# Generated by FakeRAM 2.0
VERSION 5.7 ;
BUSBITCHARS "[]" ;
PROPERTYDEFINITIONS
  MACRO width INTEGER ;
  MACRO depth INTEGER ;
  MACRO banks INTEGER ;
END PROPERTYDEFINITIONS
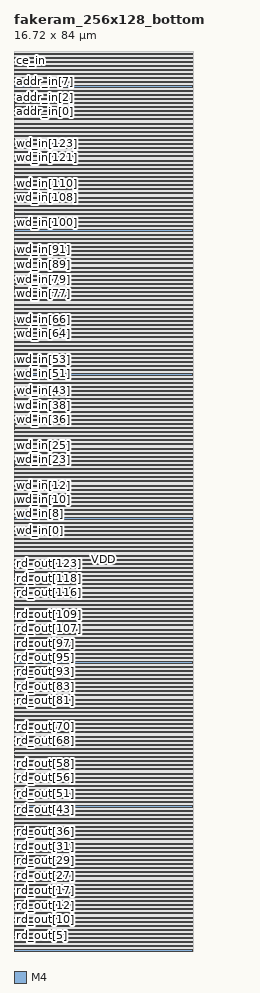
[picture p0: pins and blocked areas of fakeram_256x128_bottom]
MACRO fakeram_256x128_bottom
  PROPERTY width 128 ;
  PROPERTY depth 256 ;
  PROPERTY banks 1 ;
  FOREIGN fakeram_256x128_bottom 0 0 ;
  SYMMETRY X Y R90 ;
  SIZE 16.720 BY 84.000 ;
  CLASS BLOCK ;
  PIN rd_out[0]
    DIRECTION OUTPUT ;
    USE SIGNAL ;
    SHAPE ABUTMENT ;
    PORT
      LAYER M4 ;
      RECT 0.000 0.039 0.024 0.063 ;
    END
  END rd_out[0]
  PIN rd_out[1]
    DIRECTION OUTPUT ;
    USE SIGNAL ;
    SHAPE ABUTMENT ;
    PORT
      LAYER M4 ;
      RECT 0.000 0.327 0.024 0.351 ;
    END
  END rd_out[1]
  PIN rd_out[2]
    DIRECTION OUTPUT ;
    USE SIGNAL ;
    SHAPE ABUTMENT ;
    PORT
      LAYER M4 ;
      RECT 0.000 0.615 0.024 0.639 ;
    END
  END rd_out[2]
  PIN rd_out[3]
    DIRECTION OUTPUT ;
    USE SIGNAL ;
    SHAPE ABUTMENT ;
    PORT
      LAYER M4 ;
      RECT 0.000 0.903 0.024 0.927 ;
    END
  END rd_out[3]
  PIN rd_out[4]
    DIRECTION OUTPUT ;
    USE SIGNAL ;
    SHAPE ABUTMENT ;
    PORT
      LAYER M4 ;
      RECT 0.000 1.191 0.024 1.215 ;
    END
  END rd_out[4]
  PIN rd_out[5]
    DIRECTION OUTPUT ;
    USE SIGNAL ;
    SHAPE ABUTMENT ;
    PORT
      LAYER M4 ;
      RECT 0.000 1.479 0.024 1.503 ;
    END
  END rd_out[5]
  PIN rd_out[6]
    DIRECTION OUTPUT ;
    USE SIGNAL ;
    SHAPE ABUTMENT ;
    PORT
      LAYER M4 ;
      RECT 0.000 1.767 0.024 1.791 ;
    END
  END rd_out[6]
  PIN rd_out[7]
    DIRECTION OUTPUT ;
    USE SIGNAL ;
    SHAPE ABUTMENT ;
    PORT
      LAYER M4 ;
      RECT 0.000 2.055 0.024 2.079 ;
    END
  END rd_out[7]
  PIN rd_out[8]
    DIRECTION OUTPUT ;
    USE SIGNAL ;
    SHAPE ABUTMENT ;
    PORT
      LAYER M4 ;
      RECT 0.000 2.343 0.024 2.367 ;
    END
  END rd_out[8]
  PIN rd_out[9]
    DIRECTION OUTPUT ;
    USE SIGNAL ;
    SHAPE ABUTMENT ;
    PORT
      LAYER M4 ;
      RECT 0.000 2.631 0.024 2.655 ;
    END
  END rd_out[9]
  PIN rd_out[10]
    DIRECTION OUTPUT ;
    USE SIGNAL ;
    SHAPE ABUTMENT ;
    PORT
      LAYER M4 ;
      RECT 0.000 2.919 0.024 2.943 ;
    END
  END rd_out[10]
  PIN rd_out[11]
    DIRECTION OUTPUT ;
    USE SIGNAL ;
    SHAPE ABUTMENT ;
    PORT
      LAYER M4 ;
      RECT 0.000 3.207 0.024 3.231 ;
    END
  END rd_out[11]
  PIN rd_out[12]
    DIRECTION OUTPUT ;
    USE SIGNAL ;
    SHAPE ABUTMENT ;
    PORT
      LAYER M4 ;
      RECT 0.000 3.495 0.024 3.519 ;
    END
  END rd_out[12]
  PIN rd_out[13]
    DIRECTION OUTPUT ;
    USE SIGNAL ;
    SHAPE ABUTMENT ;
    PORT
      LAYER M4 ;
      RECT 0.000 3.783 0.024 3.807 ;
    END
  END rd_out[13]
  PIN rd_out[14]
    DIRECTION OUTPUT ;
    USE SIGNAL ;
    SHAPE ABUTMENT ;
    PORT
      LAYER M4 ;
      RECT 0.000 4.071 0.024 4.095 ;
    END
  END rd_out[14]
  PIN rd_out[15]
    DIRECTION OUTPUT ;
    USE SIGNAL ;
    SHAPE ABUTMENT ;
    PORT
      LAYER M4 ;
      RECT 0.000 4.359 0.024 4.383 ;
    END
  END rd_out[15]
  PIN rd_out[16]
    DIRECTION OUTPUT ;
    USE SIGNAL ;
    SHAPE ABUTMENT ;
    PORT
      LAYER M4 ;
      RECT 0.000 4.647 0.024 4.671 ;
    END
  END rd_out[16]
  PIN rd_out[17]
    DIRECTION OUTPUT ;
    USE SIGNAL ;
    SHAPE ABUTMENT ;
    PORT
      LAYER M4 ;
      RECT 0.000 4.935 0.024 4.959 ;
    END
  END rd_out[17]
  PIN rd_out[18]
    DIRECTION OUTPUT ;
    USE SIGNAL ;
    SHAPE ABUTMENT ;
    PORT
      LAYER M4 ;
      RECT 0.000 5.223 0.024 5.247 ;
    END
  END rd_out[18]
  PIN rd_out[19]
    DIRECTION OUTPUT ;
    USE SIGNAL ;
    SHAPE ABUTMENT ;
    PORT
      LAYER M4 ;
      RECT 0.000 5.511 0.024 5.535 ;
    END
  END rd_out[19]
  PIN rd_out[20]
    DIRECTION OUTPUT ;
    USE SIGNAL ;
    SHAPE ABUTMENT ;
    PORT
      LAYER M4 ;
      RECT 0.000 5.799 0.024 5.823 ;
    END
  END rd_out[20]
  PIN rd_out[21]
    DIRECTION OUTPUT ;
    USE SIGNAL ;
    SHAPE ABUTMENT ;
    PORT
      LAYER M4 ;
      RECT 0.000 6.087 0.024 6.111 ;
    END
  END rd_out[21]
  PIN rd_out[22]
    DIRECTION OUTPUT ;
    USE SIGNAL ;
    SHAPE ABUTMENT ;
    PORT
      LAYER M4 ;
      RECT 0.000 6.375 0.024 6.399 ;
    END
  END rd_out[22]
  PIN rd_out[23]
    DIRECTION OUTPUT ;
    USE SIGNAL ;
    SHAPE ABUTMENT ;
    PORT
      LAYER M4 ;
      RECT 0.000 6.663 0.024 6.687 ;
    END
  END rd_out[23]
  PIN rd_out[24]
    DIRECTION OUTPUT ;
    USE SIGNAL ;
    SHAPE ABUTMENT ;
    PORT
      LAYER M4 ;
      RECT 0.000 6.951 0.024 6.975 ;
    END
  END rd_out[24]
  PIN rd_out[25]
    DIRECTION OUTPUT ;
    USE SIGNAL ;
    SHAPE ABUTMENT ;
    PORT
      LAYER M4 ;
      RECT 0.000 7.239 0.024 7.263 ;
    END
  END rd_out[25]
  PIN rd_out[26]
    DIRECTION OUTPUT ;
    USE SIGNAL ;
    SHAPE ABUTMENT ;
    PORT
      LAYER M4 ;
      RECT 0.000 7.527 0.024 7.551 ;
    END
  END rd_out[26]
  PIN rd_out[27]
    DIRECTION OUTPUT ;
    USE SIGNAL ;
    SHAPE ABUTMENT ;
    PORT
      LAYER M4 ;
      RECT 0.000 7.815 0.024 7.839 ;
    END
  END rd_out[27]
  PIN rd_out[28]
    DIRECTION OUTPUT ;
    USE SIGNAL ;
    SHAPE ABUTMENT ;
    PORT
      LAYER M4 ;
      RECT 0.000 8.103 0.024 8.127 ;
    END
  END rd_out[28]
  PIN rd_out[29]
    DIRECTION OUTPUT ;
    USE SIGNAL ;
    SHAPE ABUTMENT ;
    PORT
      LAYER M4 ;
      RECT 0.000 8.391 0.024 8.415 ;
    END
  END rd_out[29]
  PIN rd_out[30]
    DIRECTION OUTPUT ;
    USE SIGNAL ;
    SHAPE ABUTMENT ;
    PORT
      LAYER M4 ;
      RECT 0.000 8.679 0.024 8.703 ;
    END
  END rd_out[30]
  PIN rd_out[31]
    DIRECTION OUTPUT ;
    USE SIGNAL ;
    SHAPE ABUTMENT ;
    PORT
      LAYER M4 ;
      RECT 0.000 8.967 0.024 8.991 ;
    END
  END rd_out[31]
  PIN rd_out[32]
    DIRECTION OUTPUT ;
    USE SIGNAL ;
    SHAPE ABUTMENT ;
    PORT
      LAYER M4 ;
      RECT 0.000 9.255 0.024 9.279 ;
    END
  END rd_out[32]
  PIN rd_out[33]
    DIRECTION OUTPUT ;
    USE SIGNAL ;
    SHAPE ABUTMENT ;
    PORT
      LAYER M4 ;
      RECT 0.000 9.543 0.024 9.567 ;
    END
  END rd_out[33]
  PIN rd_out[34]
    DIRECTION OUTPUT ;
    USE SIGNAL ;
    SHAPE ABUTMENT ;
    PORT
      LAYER M4 ;
      RECT 0.000 9.831 0.024 9.855 ;
    END
  END rd_out[34]
  PIN rd_out[35]
    DIRECTION OUTPUT ;
    USE SIGNAL ;
    SHAPE ABUTMENT ;
    PORT
      LAYER M4 ;
      RECT 0.000 10.119 0.024 10.143 ;
    END
  END rd_out[35]
  PIN rd_out[36]
    DIRECTION OUTPUT ;
    USE SIGNAL ;
    SHAPE ABUTMENT ;
    PORT
      LAYER M4 ;
      RECT 0.000 10.407 0.024 10.431 ;
    END
  END rd_out[36]
  PIN rd_out[37]
    DIRECTION OUTPUT ;
    USE SIGNAL ;
    SHAPE ABUTMENT ;
    PORT
      LAYER M4 ;
      RECT 0.000 10.695 0.024 10.719 ;
    END
  END rd_out[37]
  PIN rd_out[38]
    DIRECTION OUTPUT ;
    USE SIGNAL ;
    SHAPE ABUTMENT ;
    PORT
      LAYER M4 ;
      RECT 0.000 10.983 0.024 11.007 ;
    END
  END rd_out[38]
  PIN rd_out[39]
    DIRECTION OUTPUT ;
    USE SIGNAL ;
    SHAPE ABUTMENT ;
    PORT
      LAYER M4 ;
      RECT 0.000 11.271 0.024 11.295 ;
    END
  END rd_out[39]
  PIN rd_out[40]
    DIRECTION OUTPUT ;
    USE SIGNAL ;
    SHAPE ABUTMENT ;
    PORT
      LAYER M4 ;
      RECT 0.000 11.559 0.024 11.583 ;
    END
  END rd_out[40]
  PIN rd_out[41]
    DIRECTION OUTPUT ;
    USE SIGNAL ;
    SHAPE ABUTMENT ;
    PORT
      LAYER M4 ;
      RECT 0.000 11.847 0.024 11.871 ;
    END
  END rd_out[41]
  PIN rd_out[42]
    DIRECTION OUTPUT ;
    USE SIGNAL ;
    SHAPE ABUTMENT ;
    PORT
      LAYER M4 ;
      RECT 0.000 12.135 0.024 12.159 ;
    END
  END rd_out[42]
  PIN rd_out[43]
    DIRECTION OUTPUT ;
    USE SIGNAL ;
    SHAPE ABUTMENT ;
    PORT
      LAYER M4 ;
      RECT 0.000 12.423 0.024 12.447 ;
    END
  END rd_out[43]
  PIN rd_out[44]
    DIRECTION OUTPUT ;
    USE SIGNAL ;
    SHAPE ABUTMENT ;
    PORT
      LAYER M4 ;
      RECT 0.000 12.711 0.024 12.735 ;
    END
  END rd_out[44]
  PIN rd_out[45]
    DIRECTION OUTPUT ;
    USE SIGNAL ;
    SHAPE ABUTMENT ;
    PORT
      LAYER M4 ;
      RECT 0.000 12.999 0.024 13.023 ;
    END
  END rd_out[45]
  PIN rd_out[46]
    DIRECTION OUTPUT ;
    USE SIGNAL ;
    SHAPE ABUTMENT ;
    PORT
      LAYER M4 ;
      RECT 0.000 13.287 0.024 13.311 ;
    END
  END rd_out[46]
  PIN rd_out[47]
    DIRECTION OUTPUT ;
    USE SIGNAL ;
    SHAPE ABUTMENT ;
    PORT
      LAYER M4 ;
      RECT 0.000 13.575 0.024 13.599 ;
    END
  END rd_out[47]
  PIN rd_out[48]
    DIRECTION OUTPUT ;
    USE SIGNAL ;
    SHAPE ABUTMENT ;
    PORT
      LAYER M4 ;
      RECT 0.000 13.863 0.024 13.887 ;
    END
  END rd_out[48]
  PIN rd_out[49]
    DIRECTION OUTPUT ;
    USE SIGNAL ;
    SHAPE ABUTMENT ;
    PORT
      LAYER M4 ;
      RECT 0.000 14.151 0.024 14.175 ;
    END
  END rd_out[49]
  PIN rd_out[50]
    DIRECTION OUTPUT ;
    USE SIGNAL ;
    SHAPE ABUTMENT ;
    PORT
      LAYER M4 ;
      RECT 0.000 14.439 0.024 14.463 ;
    END
  END rd_out[50]
  PIN rd_out[51]
    DIRECTION OUTPUT ;
    USE SIGNAL ;
    SHAPE ABUTMENT ;
    PORT
      LAYER M4 ;
      RECT 0.000 14.727 0.024 14.751 ;
    END
  END rd_out[51]
  PIN rd_out[52]
    DIRECTION OUTPUT ;
    USE SIGNAL ;
    SHAPE ABUTMENT ;
    PORT
      LAYER M4 ;
      RECT 0.000 15.015 0.024 15.039 ;
    END
  END rd_out[52]
  PIN rd_out[53]
    DIRECTION OUTPUT ;
    USE SIGNAL ;
    SHAPE ABUTMENT ;
    PORT
      LAYER M4 ;
      RECT 0.000 15.303 0.024 15.327 ;
    END
  END rd_out[53]
  PIN rd_out[54]
    DIRECTION OUTPUT ;
    USE SIGNAL ;
    SHAPE ABUTMENT ;
    PORT
      LAYER M4 ;
      RECT 0.000 15.591 0.024 15.615 ;
    END
  END rd_out[54]
  PIN rd_out[55]
    DIRECTION OUTPUT ;
    USE SIGNAL ;
    SHAPE ABUTMENT ;
    PORT
      LAYER M4 ;
      RECT 0.000 15.879 0.024 15.903 ;
    END
  END rd_out[55]
  PIN rd_out[56]
    DIRECTION OUTPUT ;
    USE SIGNAL ;
    SHAPE ABUTMENT ;
    PORT
      LAYER M4 ;
      RECT 0.000 16.167 0.024 16.191 ;
    END
  END rd_out[56]
  PIN rd_out[57]
    DIRECTION OUTPUT ;
    USE SIGNAL ;
    SHAPE ABUTMENT ;
    PORT
      LAYER M4 ;
      RECT 0.000 16.455 0.024 16.479 ;
    END
  END rd_out[57]
  PIN rd_out[58]
    DIRECTION OUTPUT ;
    USE SIGNAL ;
    SHAPE ABUTMENT ;
    PORT
      LAYER M4 ;
      RECT 0.000 16.743 0.024 16.767 ;
    END
  END rd_out[58]
  PIN rd_out[59]
    DIRECTION OUTPUT ;
    USE SIGNAL ;
    SHAPE ABUTMENT ;
    PORT
      LAYER M4 ;
      RECT 0.000 17.031 0.024 17.055 ;
    END
  END rd_out[59]
  PIN rd_out[60]
    DIRECTION OUTPUT ;
    USE SIGNAL ;
    SHAPE ABUTMENT ;
    PORT
      LAYER M4 ;
      RECT 0.000 17.319 0.024 17.343 ;
    END
  END rd_out[60]
  PIN rd_out[61]
    DIRECTION OUTPUT ;
    USE SIGNAL ;
    SHAPE ABUTMENT ;
    PORT
      LAYER M4 ;
      RECT 0.000 17.607 0.024 17.631 ;
    END
  END rd_out[61]
  PIN rd_out[62]
    DIRECTION OUTPUT ;
    USE SIGNAL ;
    SHAPE ABUTMENT ;
    PORT
      LAYER M4 ;
      RECT 0.000 17.895 0.024 17.919 ;
    END
  END rd_out[62]
  PIN rd_out[63]
    DIRECTION OUTPUT ;
    USE SIGNAL ;
    SHAPE ABUTMENT ;
    PORT
      LAYER M4 ;
      RECT 0.000 18.183 0.024 18.207 ;
    END
  END rd_out[63]
  PIN rd_out[64]
    DIRECTION OUTPUT ;
    USE SIGNAL ;
    SHAPE ABUTMENT ;
    PORT
      LAYER M4 ;
      RECT 0.000 18.471 0.024 18.495 ;
    END
  END rd_out[64]
  PIN rd_out[65]
    DIRECTION OUTPUT ;
    USE SIGNAL ;
    SHAPE ABUTMENT ;
    PORT
      LAYER M4 ;
      RECT 0.000 18.759 0.024 18.783 ;
    END
  END rd_out[65]
  PIN rd_out[66]
    DIRECTION OUTPUT ;
    USE SIGNAL ;
    SHAPE ABUTMENT ;
    PORT
      LAYER M4 ;
      RECT 0.000 19.047 0.024 19.071 ;
    END
  END rd_out[66]
  PIN rd_out[67]
    DIRECTION OUTPUT ;
    USE SIGNAL ;
    SHAPE ABUTMENT ;
    PORT
      LAYER M4 ;
      RECT 0.000 19.335 0.024 19.359 ;
    END
  END rd_out[67]
  PIN rd_out[68]
    DIRECTION OUTPUT ;
    USE SIGNAL ;
    SHAPE ABUTMENT ;
    PORT
      LAYER M4 ;
      RECT 0.000 19.623 0.024 19.647 ;
    END
  END rd_out[68]
  PIN rd_out[69]
    DIRECTION OUTPUT ;
    USE SIGNAL ;
    SHAPE ABUTMENT ;
    PORT
      LAYER M4 ;
      RECT 0.000 19.911 0.024 19.935 ;
    END
  END rd_out[69]
  PIN rd_out[70]
    DIRECTION OUTPUT ;
    USE SIGNAL ;
    SHAPE ABUTMENT ;
    PORT
      LAYER M4 ;
      RECT 0.000 20.199 0.024 20.223 ;
    END
  END rd_out[70]
  PIN rd_out[71]
    DIRECTION OUTPUT ;
    USE SIGNAL ;
    SHAPE ABUTMENT ;
    PORT
      LAYER M4 ;
      RECT 0.000 20.487 0.024 20.511 ;
    END
  END rd_out[71]
  PIN rd_out[72]
    DIRECTION OUTPUT ;
    USE SIGNAL ;
    SHAPE ABUTMENT ;
    PORT
      LAYER M4 ;
      RECT 0.000 20.775 0.024 20.799 ;
    END
  END rd_out[72]
  PIN rd_out[73]
    DIRECTION OUTPUT ;
    USE SIGNAL ;
    SHAPE ABUTMENT ;
    PORT
      LAYER M4 ;
      RECT 0.000 21.063 0.024 21.087 ;
    END
  END rd_out[73]
  PIN rd_out[74]
    DIRECTION OUTPUT ;
    USE SIGNAL ;
    SHAPE ABUTMENT ;
    PORT
      LAYER M4 ;
      RECT 0.000 21.351 0.024 21.375 ;
    END
  END rd_out[74]
  PIN rd_out[75]
    DIRECTION OUTPUT ;
    USE SIGNAL ;
    SHAPE ABUTMENT ;
    PORT
      LAYER M4 ;
      RECT 0.000 21.639 0.024 21.663 ;
    END
  END rd_out[75]
  PIN rd_out[76]
    DIRECTION OUTPUT ;
    USE SIGNAL ;
    SHAPE ABUTMENT ;
    PORT
      LAYER M4 ;
      RECT 0.000 21.927 0.024 21.951 ;
    END
  END rd_out[76]
  PIN rd_out[77]
    DIRECTION OUTPUT ;
    USE SIGNAL ;
    SHAPE ABUTMENT ;
    PORT
      LAYER M4 ;
      RECT 0.000 22.215 0.024 22.239 ;
    END
  END rd_out[77]
  PIN rd_out[78]
    DIRECTION OUTPUT ;
    USE SIGNAL ;
    SHAPE ABUTMENT ;
    PORT
      LAYER M4 ;
      RECT 0.000 22.503 0.024 22.527 ;
    END
  END rd_out[78]
  PIN rd_out[79]
    DIRECTION OUTPUT ;
    USE SIGNAL ;
    SHAPE ABUTMENT ;
    PORT
      LAYER M4 ;
      RECT 0.000 22.791 0.024 22.815 ;
    END
  END rd_out[79]
  PIN rd_out[80]
    DIRECTION OUTPUT ;
    USE SIGNAL ;
    SHAPE ABUTMENT ;
    PORT
      LAYER M4 ;
      RECT 0.000 23.079 0.024 23.103 ;
    END
  END rd_out[80]
  PIN rd_out[81]
    DIRECTION OUTPUT ;
    USE SIGNAL ;
    SHAPE ABUTMENT ;
    PORT
      LAYER M4 ;
      RECT 0.000 23.367 0.024 23.391 ;
    END
  END rd_out[81]
  PIN rd_out[82]
    DIRECTION OUTPUT ;
    USE SIGNAL ;
    SHAPE ABUTMENT ;
    PORT
      LAYER M4 ;
      RECT 0.000 23.655 0.024 23.679 ;
    END
  END rd_out[82]
  PIN rd_out[83]
    DIRECTION OUTPUT ;
    USE SIGNAL ;
    SHAPE ABUTMENT ;
    PORT
      LAYER M4 ;
      RECT 0.000 23.943 0.024 23.967 ;
    END
  END rd_out[83]
  PIN rd_out[84]
    DIRECTION OUTPUT ;
    USE SIGNAL ;
    SHAPE ABUTMENT ;
    PORT
      LAYER M4 ;
      RECT 0.000 24.231 0.024 24.255 ;
    END
  END rd_out[84]
  PIN rd_out[85]
    DIRECTION OUTPUT ;
    USE SIGNAL ;
    SHAPE ABUTMENT ;
    PORT
      LAYER M4 ;
      RECT 0.000 24.519 0.024 24.543 ;
    END
  END rd_out[85]
  PIN rd_out[86]
    DIRECTION OUTPUT ;
    USE SIGNAL ;
    SHAPE ABUTMENT ;
    PORT
      LAYER M4 ;
      RECT 0.000 24.807 0.024 24.831 ;
    END
  END rd_out[86]
  PIN rd_out[87]
    DIRECTION OUTPUT ;
    USE SIGNAL ;
    SHAPE ABUTMENT ;
    PORT
      LAYER M4 ;
      RECT 0.000 25.095 0.024 25.119 ;
    END
  END rd_out[87]
  PIN rd_out[88]
    DIRECTION OUTPUT ;
    USE SIGNAL ;
    SHAPE ABUTMENT ;
    PORT
      LAYER M4 ;
      RECT 0.000 25.383 0.024 25.407 ;
    END
  END rd_out[88]
  PIN rd_out[89]
    DIRECTION OUTPUT ;
    USE SIGNAL ;
    SHAPE ABUTMENT ;
    PORT
      LAYER M4 ;
      RECT 0.000 25.671 0.024 25.695 ;
    END
  END rd_out[89]
  PIN rd_out[90]
    DIRECTION OUTPUT ;
    USE SIGNAL ;
    SHAPE ABUTMENT ;
    PORT
      LAYER M4 ;
      RECT 0.000 25.959 0.024 25.983 ;
    END
  END rd_out[90]
  PIN rd_out[91]
    DIRECTION OUTPUT ;
    USE SIGNAL ;
    SHAPE ABUTMENT ;
    PORT
      LAYER M4 ;
      RECT 0.000 26.247 0.024 26.271 ;
    END
  END rd_out[91]
  PIN rd_out[92]
    DIRECTION OUTPUT ;
    USE SIGNAL ;
    SHAPE ABUTMENT ;
    PORT
      LAYER M4 ;
      RECT 0.000 26.535 0.024 26.559 ;
    END
  END rd_out[92]
  PIN rd_out[93]
    DIRECTION OUTPUT ;
    USE SIGNAL ;
    SHAPE ABUTMENT ;
    PORT
      LAYER M4 ;
      RECT 0.000 26.823 0.024 26.847 ;
    END
  END rd_out[93]
  PIN rd_out[94]
    DIRECTION OUTPUT ;
    USE SIGNAL ;
    SHAPE ABUTMENT ;
    PORT
      LAYER M4 ;
      RECT 0.000 27.111 0.024 27.135 ;
    END
  END rd_out[94]
  PIN rd_out[95]
    DIRECTION OUTPUT ;
    USE SIGNAL ;
    SHAPE ABUTMENT ;
    PORT
      LAYER M4 ;
      RECT 0.000 27.399 0.024 27.423 ;
    END
  END rd_out[95]
  PIN rd_out[96]
    DIRECTION OUTPUT ;
    USE SIGNAL ;
    SHAPE ABUTMENT ;
    PORT
      LAYER M4 ;
      RECT 0.000 27.687 0.024 27.711 ;
    END
  END rd_out[96]
  PIN rd_out[97]
    DIRECTION OUTPUT ;
    USE SIGNAL ;
    SHAPE ABUTMENT ;
    PORT
      LAYER M4 ;
      RECT 0.000 27.975 0.024 27.999 ;
    END
  END rd_out[97]
  PIN rd_out[98]
    DIRECTION OUTPUT ;
    USE SIGNAL ;
    SHAPE ABUTMENT ;
    PORT
      LAYER M4 ;
      RECT 0.000 28.263 0.024 28.287 ;
    END
  END rd_out[98]
  PIN rd_out[99]
    DIRECTION OUTPUT ;
    USE SIGNAL ;
    SHAPE ABUTMENT ;
    PORT
      LAYER M4 ;
      RECT 0.000 28.551 0.024 28.575 ;
    END
  END rd_out[99]
  PIN rd_out[100]
    DIRECTION OUTPUT ;
    USE SIGNAL ;
    SHAPE ABUTMENT ;
    PORT
      LAYER M4 ;
      RECT 0.000 28.839 0.024 28.863 ;
    END
  END rd_out[100]
  PIN rd_out[101]
    DIRECTION OUTPUT ;
    USE SIGNAL ;
    SHAPE ABUTMENT ;
    PORT
      LAYER M4 ;
      RECT 0.000 29.127 0.024 29.151 ;
    END
  END rd_out[101]
  PIN rd_out[102]
    DIRECTION OUTPUT ;
    USE SIGNAL ;
    SHAPE ABUTMENT ;
    PORT
      LAYER M4 ;
      RECT 0.000 29.415 0.024 29.439 ;
    END
  END rd_out[102]
  PIN rd_out[103]
    DIRECTION OUTPUT ;
    USE SIGNAL ;
    SHAPE ABUTMENT ;
    PORT
      LAYER M4 ;
      RECT 0.000 29.703 0.024 29.727 ;
    END
  END rd_out[103]
  PIN rd_out[104]
    DIRECTION OUTPUT ;
    USE SIGNAL ;
    SHAPE ABUTMENT ;
    PORT
      LAYER M4 ;
      RECT 0.000 29.991 0.024 30.015 ;
    END
  END rd_out[104]
  PIN rd_out[105]
    DIRECTION OUTPUT ;
    USE SIGNAL ;
    SHAPE ABUTMENT ;
    PORT
      LAYER M4 ;
      RECT 0.000 30.279 0.024 30.303 ;
    END
  END rd_out[105]
  PIN rd_out[106]
    DIRECTION OUTPUT ;
    USE SIGNAL ;
    SHAPE ABUTMENT ;
    PORT
      LAYER M4 ;
      RECT 0.000 30.567 0.024 30.591 ;
    END
  END rd_out[106]
  PIN rd_out[107]
    DIRECTION OUTPUT ;
    USE SIGNAL ;
    SHAPE ABUTMENT ;
    PORT
      LAYER M4 ;
      RECT 0.000 30.855 0.024 30.879 ;
    END
  END rd_out[107]
  PIN rd_out[108]
    DIRECTION OUTPUT ;
    USE SIGNAL ;
    SHAPE ABUTMENT ;
    PORT
      LAYER M4 ;
      RECT 0.000 31.143 0.024 31.167 ;
    END
  END rd_out[108]
  PIN rd_out[109]
    DIRECTION OUTPUT ;
    USE SIGNAL ;
    SHAPE ABUTMENT ;
    PORT
      LAYER M4 ;
      RECT 0.000 31.431 0.024 31.455 ;
    END
  END rd_out[109]
  PIN rd_out[110]
    DIRECTION OUTPUT ;
    USE SIGNAL ;
    SHAPE ABUTMENT ;
    PORT
      LAYER M4 ;
      RECT 0.000 31.719 0.024 31.743 ;
    END
  END rd_out[110]
  PIN rd_out[111]
    DIRECTION OUTPUT ;
    USE SIGNAL ;
    SHAPE ABUTMENT ;
    PORT
      LAYER M4 ;
      RECT 0.000 32.007 0.024 32.031 ;
    END
  END rd_out[111]
  PIN rd_out[112]
    DIRECTION OUTPUT ;
    USE SIGNAL ;
    SHAPE ABUTMENT ;
    PORT
      LAYER M4 ;
      RECT 0.000 32.295 0.024 32.319 ;
    END
  END rd_out[112]
  PIN rd_out[113]
    DIRECTION OUTPUT ;
    USE SIGNAL ;
    SHAPE ABUTMENT ;
    PORT
      LAYER M4 ;
      RECT 0.000 32.583 0.024 32.607 ;
    END
  END rd_out[113]
  PIN rd_out[114]
    DIRECTION OUTPUT ;
    USE SIGNAL ;
    SHAPE ABUTMENT ;
    PORT
      LAYER M4 ;
      RECT 0.000 32.871 0.024 32.895 ;
    END
  END rd_out[114]
  PIN rd_out[115]
    DIRECTION OUTPUT ;
    USE SIGNAL ;
    SHAPE ABUTMENT ;
    PORT
      LAYER M4 ;
      RECT 0.000 33.159 0.024 33.183 ;
    END
  END rd_out[115]
  PIN rd_out[116]
    DIRECTION OUTPUT ;
    USE SIGNAL ;
    SHAPE ABUTMENT ;
    PORT
      LAYER M4 ;
      RECT 0.000 33.447 0.024 33.471 ;
    END
  END rd_out[116]
  PIN rd_out[117]
    DIRECTION OUTPUT ;
    USE SIGNAL ;
    SHAPE ABUTMENT ;
    PORT
      LAYER M4 ;
      RECT 0.000 33.735 0.024 33.759 ;
    END
  END rd_out[117]
  PIN rd_out[118]
    DIRECTION OUTPUT ;
    USE SIGNAL ;
    SHAPE ABUTMENT ;
    PORT
      LAYER M4 ;
      RECT 0.000 34.023 0.024 34.047 ;
    END
  END rd_out[118]
  PIN rd_out[119]
    DIRECTION OUTPUT ;
    USE SIGNAL ;
    SHAPE ABUTMENT ;
    PORT
      LAYER M4 ;
      RECT 0.000 34.311 0.024 34.335 ;
    END
  END rd_out[119]
  PIN rd_out[120]
    DIRECTION OUTPUT ;
    USE SIGNAL ;
    SHAPE ABUTMENT ;
    PORT
      LAYER M4 ;
      RECT 0.000 34.599 0.024 34.623 ;
    END
  END rd_out[120]
  PIN rd_out[121]
    DIRECTION OUTPUT ;
    USE SIGNAL ;
    SHAPE ABUTMENT ;
    PORT
      LAYER M4 ;
      RECT 0.000 34.887 0.024 34.911 ;
    END
  END rd_out[121]
  PIN rd_out[122]
    DIRECTION OUTPUT ;
    USE SIGNAL ;
    SHAPE ABUTMENT ;
    PORT
      LAYER M4 ;
      RECT 0.000 35.175 0.024 35.199 ;
    END
  END rd_out[122]
  PIN rd_out[123]
    DIRECTION OUTPUT ;
    USE SIGNAL ;
    SHAPE ABUTMENT ;
    PORT
      LAYER M4 ;
      RECT 0.000 35.463 0.024 35.487 ;
    END
  END rd_out[123]
  PIN rd_out[124]
    DIRECTION OUTPUT ;
    USE SIGNAL ;
    SHAPE ABUTMENT ;
    PORT
      LAYER M4 ;
      RECT 0.000 35.751 0.024 35.775 ;
    END
  END rd_out[124]
  PIN rd_out[125]
    DIRECTION OUTPUT ;
    USE SIGNAL ;
    SHAPE ABUTMENT ;
    PORT
      LAYER M4 ;
      RECT 0.000 36.039 0.024 36.063 ;
    END
  END rd_out[125]
  PIN rd_out[126]
    DIRECTION OUTPUT ;
    USE SIGNAL ;
    SHAPE ABUTMENT ;
    PORT
      LAYER M4 ;
      RECT 0.000 36.327 0.024 36.351 ;
    END
  END rd_out[126]
  PIN rd_out[127]
    DIRECTION OUTPUT ;
    USE SIGNAL ;
    SHAPE ABUTMENT ;
    PORT
      LAYER M4 ;
      RECT 0.000 36.615 0.024 36.639 ;
    END
  END rd_out[127]
  PIN wd_in[0]
    DIRECTION INPUT ;
    USE SIGNAL ;
    SHAPE ABUTMENT ;
    PORT
      LAYER M4 ;
      RECT 0.000 39.207 0.024 39.231 ;
    END
  END wd_in[0]
  PIN wd_in[1]
    DIRECTION INPUT ;
    USE SIGNAL ;
    SHAPE ABUTMENT ;
    PORT
      LAYER M4 ;
      RECT 0.000 39.495 0.024 39.519 ;
    END
  END wd_in[1]
  PIN wd_in[2]
    DIRECTION INPUT ;
    USE SIGNAL ;
    SHAPE ABUTMENT ;
    PORT
      LAYER M4 ;
      RECT 0.000 39.783 0.024 39.807 ;
    END
  END wd_in[2]
  PIN wd_in[3]
    DIRECTION INPUT ;
    USE SIGNAL ;
    SHAPE ABUTMENT ;
    PORT
      LAYER M4 ;
      RECT 0.000 40.071 0.024 40.095 ;
    END
  END wd_in[3]
  PIN wd_in[4]
    DIRECTION INPUT ;
    USE SIGNAL ;
    SHAPE ABUTMENT ;
    PORT
      LAYER M4 ;
      RECT 0.000 40.359 0.024 40.383 ;
    END
  END wd_in[4]
  PIN wd_in[5]
    DIRECTION INPUT ;
    USE SIGNAL ;
    SHAPE ABUTMENT ;
    PORT
      LAYER M4 ;
      RECT 0.000 40.647 0.024 40.671 ;
    END
  END wd_in[5]
  PIN wd_in[6]
    DIRECTION INPUT ;
    USE SIGNAL ;
    SHAPE ABUTMENT ;
    PORT
      LAYER M4 ;
      RECT 0.000 40.935 0.024 40.959 ;
    END
  END wd_in[6]
  PIN wd_in[7]
    DIRECTION INPUT ;
    USE SIGNAL ;
    SHAPE ABUTMENT ;
    PORT
      LAYER M4 ;
      RECT 0.000 41.223 0.024 41.247 ;
    END
  END wd_in[7]
  PIN wd_in[8]
    DIRECTION INPUT ;
    USE SIGNAL ;
    SHAPE ABUTMENT ;
    PORT
      LAYER M4 ;
      RECT 0.000 41.511 0.024 41.535 ;
    END
  END wd_in[8]
  PIN wd_in[9]
    DIRECTION INPUT ;
    USE SIGNAL ;
    SHAPE ABUTMENT ;
    PORT
      LAYER M4 ;
      RECT 0.000 41.799 0.024 41.823 ;
    END
  END wd_in[9]
  PIN wd_in[10]
    DIRECTION INPUT ;
    USE SIGNAL ;
    SHAPE ABUTMENT ;
    PORT
      LAYER M4 ;
      RECT 0.000 42.087 0.024 42.111 ;
    END
  END wd_in[10]
  PIN wd_in[11]
    DIRECTION INPUT ;
    USE SIGNAL ;
    SHAPE ABUTMENT ;
    PORT
      LAYER M4 ;
      RECT 0.000 42.375 0.024 42.399 ;
    END
  END wd_in[11]
  PIN wd_in[12]
    DIRECTION INPUT ;
    USE SIGNAL ;
    SHAPE ABUTMENT ;
    PORT
      LAYER M4 ;
      RECT 0.000 42.663 0.024 42.687 ;
    END
  END wd_in[12]
  PIN wd_in[13]
    DIRECTION INPUT ;
    USE SIGNAL ;
    SHAPE ABUTMENT ;
    PORT
      LAYER M4 ;
      RECT 0.000 42.951 0.024 42.975 ;
    END
  END wd_in[13]
  PIN wd_in[14]
    DIRECTION INPUT ;
    USE SIGNAL ;
    SHAPE ABUTMENT ;
    PORT
      LAYER M4 ;
      RECT 0.000 43.239 0.024 43.263 ;
    END
  END wd_in[14]
  PIN wd_in[15]
    DIRECTION INPUT ;
    USE SIGNAL ;
    SHAPE ABUTMENT ;
    PORT
      LAYER M4 ;
      RECT 0.000 43.527 0.024 43.551 ;
    END
  END wd_in[15]
  PIN wd_in[16]
    DIRECTION INPUT ;
    USE SIGNAL ;
    SHAPE ABUTMENT ;
    PORT
      LAYER M4 ;
      RECT 0.000 43.815 0.024 43.839 ;
    END
  END wd_in[16]
  PIN wd_in[17]
    DIRECTION INPUT ;
    USE SIGNAL ;
    SHAPE ABUTMENT ;
    PORT
      LAYER M4 ;
      RECT 0.000 44.103 0.024 44.127 ;
    END
  END wd_in[17]
  PIN wd_in[18]
    DIRECTION INPUT ;
    USE SIGNAL ;
    SHAPE ABUTMENT ;
    PORT
      LAYER M4 ;
      RECT 0.000 44.391 0.024 44.415 ;
    END
  END wd_in[18]
  PIN wd_in[19]
    DIRECTION INPUT ;
    USE SIGNAL ;
    SHAPE ABUTMENT ;
    PORT
      LAYER M4 ;
      RECT 0.000 44.679 0.024 44.703 ;
    END
  END wd_in[19]
  PIN wd_in[20]
    DIRECTION INPUT ;
    USE SIGNAL ;
    SHAPE ABUTMENT ;
    PORT
      LAYER M4 ;
      RECT 0.000 44.967 0.024 44.991 ;
    END
  END wd_in[20]
  PIN wd_in[21]
    DIRECTION INPUT ;
    USE SIGNAL ;
    SHAPE ABUTMENT ;
    PORT
      LAYER M4 ;
      RECT 0.000 45.255 0.024 45.279 ;
    END
  END wd_in[21]
  PIN wd_in[22]
    DIRECTION INPUT ;
    USE SIGNAL ;
    SHAPE ABUTMENT ;
    PORT
      LAYER M4 ;
      RECT 0.000 45.543 0.024 45.567 ;
    END
  END wd_in[22]
  PIN wd_in[23]
    DIRECTION INPUT ;
    USE SIGNAL ;
    SHAPE ABUTMENT ;
    PORT
      LAYER M4 ;
      RECT 0.000 45.831 0.024 45.855 ;
    END
  END wd_in[23]
  PIN wd_in[24]
    DIRECTION INPUT ;
    USE SIGNAL ;
    SHAPE ABUTMENT ;
    PORT
      LAYER M4 ;
      RECT 0.000 46.119 0.024 46.143 ;
    END
  END wd_in[24]
  PIN wd_in[25]
    DIRECTION INPUT ;
    USE SIGNAL ;
    SHAPE ABUTMENT ;
    PORT
      LAYER M4 ;
      RECT 0.000 46.407 0.024 46.431 ;
    END
  END wd_in[25]
  PIN wd_in[26]
    DIRECTION INPUT ;
    USE SIGNAL ;
    SHAPE ABUTMENT ;
    PORT
      LAYER M4 ;
      RECT 0.000 46.695 0.024 46.719 ;
    END
  END wd_in[26]
  PIN wd_in[27]
    DIRECTION INPUT ;
    USE SIGNAL ;
    SHAPE ABUTMENT ;
    PORT
      LAYER M4 ;
      RECT 0.000 46.983 0.024 47.007 ;
    END
  END wd_in[27]
  PIN wd_in[28]
    DIRECTION INPUT ;
    USE SIGNAL ;
    SHAPE ABUTMENT ;
    PORT
      LAYER M4 ;
      RECT 0.000 47.271 0.024 47.295 ;
    END
  END wd_in[28]
  PIN wd_in[29]
    DIRECTION INPUT ;
    USE SIGNAL ;
    SHAPE ABUTMENT ;
    PORT
      LAYER M4 ;
      RECT 0.000 47.559 0.024 47.583 ;
    END
  END wd_in[29]
  PIN wd_in[30]
    DIRECTION INPUT ;
    USE SIGNAL ;
    SHAPE ABUTMENT ;
    PORT
      LAYER M4 ;
      RECT 0.000 47.847 0.024 47.871 ;
    END
  END wd_in[30]
  PIN wd_in[31]
    DIRECTION INPUT ;
    USE SIGNAL ;
    SHAPE ABUTMENT ;
    PORT
      LAYER M4 ;
      RECT 0.000 48.135 0.024 48.159 ;
    END
  END wd_in[31]
  PIN wd_in[32]
    DIRECTION INPUT ;
    USE SIGNAL ;
    SHAPE ABUTMENT ;
    PORT
      LAYER M4 ;
      RECT 0.000 48.423 0.024 48.447 ;
    END
  END wd_in[32]
  PIN wd_in[33]
    DIRECTION INPUT ;
    USE SIGNAL ;
    SHAPE ABUTMENT ;
    PORT
      LAYER M4 ;
      RECT 0.000 48.711 0.024 48.735 ;
    END
  END wd_in[33]
  PIN wd_in[34]
    DIRECTION INPUT ;
    USE SIGNAL ;
    SHAPE ABUTMENT ;
    PORT
      LAYER M4 ;
      RECT 0.000 48.999 0.024 49.023 ;
    END
  END wd_in[34]
  PIN wd_in[35]
    DIRECTION INPUT ;
    USE SIGNAL ;
    SHAPE ABUTMENT ;
    PORT
      LAYER M4 ;
      RECT 0.000 49.287 0.024 49.311 ;
    END
  END wd_in[35]
  PIN wd_in[36]
    DIRECTION INPUT ;
    USE SIGNAL ;
    SHAPE ABUTMENT ;
    PORT
      LAYER M4 ;
      RECT 0.000 49.575 0.024 49.599 ;
    END
  END wd_in[36]
  PIN wd_in[37]
    DIRECTION INPUT ;
    USE SIGNAL ;
    SHAPE ABUTMENT ;
    PORT
      LAYER M4 ;
      RECT 0.000 49.863 0.024 49.887 ;
    END
  END wd_in[37]
  PIN wd_in[38]
    DIRECTION INPUT ;
    USE SIGNAL ;
    SHAPE ABUTMENT ;
    PORT
      LAYER M4 ;
      RECT 0.000 50.151 0.024 50.175 ;
    END
  END wd_in[38]
  PIN wd_in[39]
    DIRECTION INPUT ;
    USE SIGNAL ;
    SHAPE ABUTMENT ;
    PORT
      LAYER M4 ;
      RECT 0.000 50.439 0.024 50.463 ;
    END
  END wd_in[39]
  PIN wd_in[40]
    DIRECTION INPUT ;
    USE SIGNAL ;
    SHAPE ABUTMENT ;
    PORT
      LAYER M4 ;
      RECT 0.000 50.727 0.024 50.751 ;
    END
  END wd_in[40]
  PIN wd_in[41]
    DIRECTION INPUT ;
    USE SIGNAL ;
    SHAPE ABUTMENT ;
    PORT
      LAYER M4 ;
      RECT 0.000 51.015 0.024 51.039 ;
    END
  END wd_in[41]
  PIN wd_in[42]
    DIRECTION INPUT ;
    USE SIGNAL ;
    SHAPE ABUTMENT ;
    PORT
      LAYER M4 ;
      RECT 0.000 51.303 0.024 51.327 ;
    END
  END wd_in[42]
  PIN wd_in[43]
    DIRECTION INPUT ;
    USE SIGNAL ;
    SHAPE ABUTMENT ;
    PORT
      LAYER M4 ;
      RECT 0.000 51.591 0.024 51.615 ;
    END
  END wd_in[43]
  PIN wd_in[44]
    DIRECTION INPUT ;
    USE SIGNAL ;
    SHAPE ABUTMENT ;
    PORT
      LAYER M4 ;
      RECT 0.000 51.879 0.024 51.903 ;
    END
  END wd_in[44]
  PIN wd_in[45]
    DIRECTION INPUT ;
    USE SIGNAL ;
    SHAPE ABUTMENT ;
    PORT
      LAYER M4 ;
      RECT 0.000 52.167 0.024 52.191 ;
    END
  END wd_in[45]
  PIN wd_in[46]
    DIRECTION INPUT ;
    USE SIGNAL ;
    SHAPE ABUTMENT ;
    PORT
      LAYER M4 ;
      RECT 0.000 52.455 0.024 52.479 ;
    END
  END wd_in[46]
  PIN wd_in[47]
    DIRECTION INPUT ;
    USE SIGNAL ;
    SHAPE ABUTMENT ;
    PORT
      LAYER M4 ;
      RECT 0.000 52.743 0.024 52.767 ;
    END
  END wd_in[47]
  PIN wd_in[48]
    DIRECTION INPUT ;
    USE SIGNAL ;
    SHAPE ABUTMENT ;
    PORT
      LAYER M4 ;
      RECT 0.000 53.031 0.024 53.055 ;
    END
  END wd_in[48]
  PIN wd_in[49]
    DIRECTION INPUT ;
    USE SIGNAL ;
    SHAPE ABUTMENT ;
    PORT
      LAYER M4 ;
      RECT 0.000 53.319 0.024 53.343 ;
    END
  END wd_in[49]
  PIN wd_in[50]
    DIRECTION INPUT ;
    USE SIGNAL ;
    SHAPE ABUTMENT ;
    PORT
      LAYER M4 ;
      RECT 0.000 53.607 0.024 53.631 ;
    END
  END wd_in[50]
  PIN wd_in[51]
    DIRECTION INPUT ;
    USE SIGNAL ;
    SHAPE ABUTMENT ;
    PORT
      LAYER M4 ;
      RECT 0.000 53.895 0.024 53.919 ;
    END
  END wd_in[51]
  PIN wd_in[52]
    DIRECTION INPUT ;
    USE SIGNAL ;
    SHAPE ABUTMENT ;
    PORT
      LAYER M4 ;
      RECT 0.000 54.183 0.024 54.207 ;
    END
  END wd_in[52]
  PIN wd_in[53]
    DIRECTION INPUT ;
    USE SIGNAL ;
    SHAPE ABUTMENT ;
    PORT
      LAYER M4 ;
      RECT 0.000 54.471 0.024 54.495 ;
    END
  END wd_in[53]
  PIN wd_in[54]
    DIRECTION INPUT ;
    USE SIGNAL ;
    SHAPE ABUTMENT ;
    PORT
      LAYER M4 ;
      RECT 0.000 54.759 0.024 54.783 ;
    END
  END wd_in[54]
  PIN wd_in[55]
    DIRECTION INPUT ;
    USE SIGNAL ;
    SHAPE ABUTMENT ;
    PORT
      LAYER M4 ;
      RECT 0.000 55.047 0.024 55.071 ;
    END
  END wd_in[55]
  PIN wd_in[56]
    DIRECTION INPUT ;
    USE SIGNAL ;
    SHAPE ABUTMENT ;
    PORT
      LAYER M4 ;
      RECT 0.000 55.335 0.024 55.359 ;
    END
  END wd_in[56]
  PIN wd_in[57]
    DIRECTION INPUT ;
    USE SIGNAL ;
    SHAPE ABUTMENT ;
    PORT
      LAYER M4 ;
      RECT 0.000 55.623 0.024 55.647 ;
    END
  END wd_in[57]
  PIN wd_in[58]
    DIRECTION INPUT ;
    USE SIGNAL ;
    SHAPE ABUTMENT ;
    PORT
      LAYER M4 ;
      RECT 0.000 55.911 0.024 55.935 ;
    END
  END wd_in[58]
  PIN wd_in[59]
    DIRECTION INPUT ;
    USE SIGNAL ;
    SHAPE ABUTMENT ;
    PORT
      LAYER M4 ;
      RECT 0.000 56.199 0.024 56.223 ;
    END
  END wd_in[59]
  PIN wd_in[60]
    DIRECTION INPUT ;
    USE SIGNAL ;
    SHAPE ABUTMENT ;
    PORT
      LAYER M4 ;
      RECT 0.000 56.487 0.024 56.511 ;
    END
  END wd_in[60]
  PIN wd_in[61]
    DIRECTION INPUT ;
    USE SIGNAL ;
    SHAPE ABUTMENT ;
    PORT
      LAYER M4 ;
      RECT 0.000 56.775 0.024 56.799 ;
    END
  END wd_in[61]
  PIN wd_in[62]
    DIRECTION INPUT ;
    USE SIGNAL ;
    SHAPE ABUTMENT ;
    PORT
      LAYER M4 ;
      RECT 0.000 57.063 0.024 57.087 ;
    END
  END wd_in[62]
  PIN wd_in[63]
    DIRECTION INPUT ;
    USE SIGNAL ;
    SHAPE ABUTMENT ;
    PORT
      LAYER M4 ;
      RECT 0.000 57.351 0.024 57.375 ;
    END
  END wd_in[63]
  PIN wd_in[64]
    DIRECTION INPUT ;
    USE SIGNAL ;
    SHAPE ABUTMENT ;
    PORT
      LAYER M4 ;
      RECT 0.000 57.639 0.024 57.663 ;
    END
  END wd_in[64]
  PIN wd_in[65]
    DIRECTION INPUT ;
    USE SIGNAL ;
    SHAPE ABUTMENT ;
    PORT
      LAYER M4 ;
      RECT 0.000 57.927 0.024 57.951 ;
    END
  END wd_in[65]
  PIN wd_in[66]
    DIRECTION INPUT ;
    USE SIGNAL ;
    SHAPE ABUTMENT ;
    PORT
      LAYER M4 ;
      RECT 0.000 58.215 0.024 58.239 ;
    END
  END wd_in[66]
  PIN wd_in[67]
    DIRECTION INPUT ;
    USE SIGNAL ;
    SHAPE ABUTMENT ;
    PORT
      LAYER M4 ;
      RECT 0.000 58.503 0.024 58.527 ;
    END
  END wd_in[67]
  PIN wd_in[68]
    DIRECTION INPUT ;
    USE SIGNAL ;
    SHAPE ABUTMENT ;
    PORT
      LAYER M4 ;
      RECT 0.000 58.791 0.024 58.815 ;
    END
  END wd_in[68]
  PIN wd_in[69]
    DIRECTION INPUT ;
    USE SIGNAL ;
    SHAPE ABUTMENT ;
    PORT
      LAYER M4 ;
      RECT 0.000 59.079 0.024 59.103 ;
    END
  END wd_in[69]
  PIN wd_in[70]
    DIRECTION INPUT ;
    USE SIGNAL ;
    SHAPE ABUTMENT ;
    PORT
      LAYER M4 ;
      RECT 0.000 59.367 0.024 59.391 ;
    END
  END wd_in[70]
  PIN wd_in[71]
    DIRECTION INPUT ;
    USE SIGNAL ;
    SHAPE ABUTMENT ;
    PORT
      LAYER M4 ;
      RECT 0.000 59.655 0.024 59.679 ;
    END
  END wd_in[71]
  PIN wd_in[72]
    DIRECTION INPUT ;
    USE SIGNAL ;
    SHAPE ABUTMENT ;
    PORT
      LAYER M4 ;
      RECT 0.000 59.943 0.024 59.967 ;
    END
  END wd_in[72]
  PIN wd_in[73]
    DIRECTION INPUT ;
    USE SIGNAL ;
    SHAPE ABUTMENT ;
    PORT
      LAYER M4 ;
      RECT 0.000 60.231 0.024 60.255 ;
    END
  END wd_in[73]
  PIN wd_in[74]
    DIRECTION INPUT ;
    USE SIGNAL ;
    SHAPE ABUTMENT ;
    PORT
      LAYER M4 ;
      RECT 0.000 60.519 0.024 60.543 ;
    END
  END wd_in[74]
  PIN wd_in[75]
    DIRECTION INPUT ;
    USE SIGNAL ;
    SHAPE ABUTMENT ;
    PORT
      LAYER M4 ;
      RECT 0.000 60.807 0.024 60.831 ;
    END
  END wd_in[75]
  PIN wd_in[76]
    DIRECTION INPUT ;
    USE SIGNAL ;
    SHAPE ABUTMENT ;
    PORT
      LAYER M4 ;
      RECT 0.000 61.095 0.024 61.119 ;
    END
  END wd_in[76]
  PIN wd_in[77]
    DIRECTION INPUT ;
    USE SIGNAL ;
    SHAPE ABUTMENT ;
    PORT
      LAYER M4 ;
      RECT 0.000 61.383 0.024 61.407 ;
    END
  END wd_in[77]
  PIN wd_in[78]
    DIRECTION INPUT ;
    USE SIGNAL ;
    SHAPE ABUTMENT ;
    PORT
      LAYER M4 ;
      RECT 0.000 61.671 0.024 61.695 ;
    END
  END wd_in[78]
  PIN wd_in[79]
    DIRECTION INPUT ;
    USE SIGNAL ;
    SHAPE ABUTMENT ;
    PORT
      LAYER M4 ;
      RECT 0.000 61.959 0.024 61.983 ;
    END
  END wd_in[79]
  PIN wd_in[80]
    DIRECTION INPUT ;
    USE SIGNAL ;
    SHAPE ABUTMENT ;
    PORT
      LAYER M4 ;
      RECT 0.000 62.247 0.024 62.271 ;
    END
  END wd_in[80]
  PIN wd_in[81]
    DIRECTION INPUT ;
    USE SIGNAL ;
    SHAPE ABUTMENT ;
    PORT
      LAYER M4 ;
      RECT 0.000 62.535 0.024 62.559 ;
    END
  END wd_in[81]
  PIN wd_in[82]
    DIRECTION INPUT ;
    USE SIGNAL ;
    SHAPE ABUTMENT ;
    PORT
      LAYER M4 ;
      RECT 0.000 62.823 0.024 62.847 ;
    END
  END wd_in[82]
  PIN wd_in[83]
    DIRECTION INPUT ;
    USE SIGNAL ;
    SHAPE ABUTMENT ;
    PORT
      LAYER M4 ;
      RECT 0.000 63.111 0.024 63.135 ;
    END
  END wd_in[83]
  PIN wd_in[84]
    DIRECTION INPUT ;
    USE SIGNAL ;
    SHAPE ABUTMENT ;
    PORT
      LAYER M4 ;
      RECT 0.000 63.399 0.024 63.423 ;
    END
  END wd_in[84]
  PIN wd_in[85]
    DIRECTION INPUT ;
    USE SIGNAL ;
    SHAPE ABUTMENT ;
    PORT
      LAYER M4 ;
      RECT 0.000 63.687 0.024 63.711 ;
    END
  END wd_in[85]
  PIN wd_in[86]
    DIRECTION INPUT ;
    USE SIGNAL ;
    SHAPE ABUTMENT ;
    PORT
      LAYER M4 ;
      RECT 0.000 63.975 0.024 63.999 ;
    END
  END wd_in[86]
  PIN wd_in[87]
    DIRECTION INPUT ;
    USE SIGNAL ;
    SHAPE ABUTMENT ;
    PORT
      LAYER M4 ;
      RECT 0.000 64.263 0.024 64.287 ;
    END
  END wd_in[87]
  PIN wd_in[88]
    DIRECTION INPUT ;
    USE SIGNAL ;
    SHAPE ABUTMENT ;
    PORT
      LAYER M4 ;
      RECT 0.000 64.551 0.024 64.575 ;
    END
  END wd_in[88]
  PIN wd_in[89]
    DIRECTION INPUT ;
    USE SIGNAL ;
    SHAPE ABUTMENT ;
    PORT
      LAYER M4 ;
      RECT 0.000 64.839 0.024 64.863 ;
    END
  END wd_in[89]
  PIN wd_in[90]
    DIRECTION INPUT ;
    USE SIGNAL ;
    SHAPE ABUTMENT ;
    PORT
      LAYER M4 ;
      RECT 0.000 65.127 0.024 65.151 ;
    END
  END wd_in[90]
  PIN wd_in[91]
    DIRECTION INPUT ;
    USE SIGNAL ;
    SHAPE ABUTMENT ;
    PORT
      LAYER M4 ;
      RECT 0.000 65.415 0.024 65.439 ;
    END
  END wd_in[91]
  PIN wd_in[92]
    DIRECTION INPUT ;
    USE SIGNAL ;
    SHAPE ABUTMENT ;
    PORT
      LAYER M4 ;
      RECT 0.000 65.703 0.024 65.727 ;
    END
  END wd_in[92]
  PIN wd_in[93]
    DIRECTION INPUT ;
    USE SIGNAL ;
    SHAPE ABUTMENT ;
    PORT
      LAYER M4 ;
      RECT 0.000 65.991 0.024 66.015 ;
    END
  END wd_in[93]
  PIN wd_in[94]
    DIRECTION INPUT ;
    USE SIGNAL ;
    SHAPE ABUTMENT ;
    PORT
      LAYER M4 ;
      RECT 0.000 66.279 0.024 66.303 ;
    END
  END wd_in[94]
  PIN wd_in[95]
    DIRECTION INPUT ;
    USE SIGNAL ;
    SHAPE ABUTMENT ;
    PORT
      LAYER M4 ;
      RECT 0.000 66.567 0.024 66.591 ;
    END
  END wd_in[95]
  PIN wd_in[96]
    DIRECTION INPUT ;
    USE SIGNAL ;
    SHAPE ABUTMENT ;
    PORT
      LAYER M4 ;
      RECT 0.000 66.855 0.024 66.879 ;
    END
  END wd_in[96]
  PIN wd_in[97]
    DIRECTION INPUT ;
    USE SIGNAL ;
    SHAPE ABUTMENT ;
    PORT
      LAYER M4 ;
      RECT 0.000 67.143 0.024 67.167 ;
    END
  END wd_in[97]
  PIN wd_in[98]
    DIRECTION INPUT ;
    USE SIGNAL ;
    SHAPE ABUTMENT ;
    PORT
      LAYER M4 ;
      RECT 0.000 67.431 0.024 67.455 ;
    END
  END wd_in[98]
  PIN wd_in[99]
    DIRECTION INPUT ;
    USE SIGNAL ;
    SHAPE ABUTMENT ;
    PORT
      LAYER M4 ;
      RECT 0.000 67.719 0.024 67.743 ;
    END
  END wd_in[99]
  PIN wd_in[100]
    DIRECTION INPUT ;
    USE SIGNAL ;
    SHAPE ABUTMENT ;
    PORT
      LAYER M4 ;
      RECT 0.000 68.007 0.024 68.031 ;
    END
  END wd_in[100]
  PIN wd_in[101]
    DIRECTION INPUT ;
    USE SIGNAL ;
    SHAPE ABUTMENT ;
    PORT
      LAYER M4 ;
      RECT 0.000 68.295 0.024 68.319 ;
    END
  END wd_in[101]
  PIN wd_in[102]
    DIRECTION INPUT ;
    USE SIGNAL ;
    SHAPE ABUTMENT ;
    PORT
      LAYER M4 ;
      RECT 0.000 68.583 0.024 68.607 ;
    END
  END wd_in[102]
  PIN wd_in[103]
    DIRECTION INPUT ;
    USE SIGNAL ;
    SHAPE ABUTMENT ;
    PORT
      LAYER M4 ;
      RECT 0.000 68.871 0.024 68.895 ;
    END
  END wd_in[103]
  PIN wd_in[104]
    DIRECTION INPUT ;
    USE SIGNAL ;
    SHAPE ABUTMENT ;
    PORT
      LAYER M4 ;
      RECT 0.000 69.159 0.024 69.183 ;
    END
  END wd_in[104]
  PIN wd_in[105]
    DIRECTION INPUT ;
    USE SIGNAL ;
    SHAPE ABUTMENT ;
    PORT
      LAYER M4 ;
      RECT 0.000 69.447 0.024 69.471 ;
    END
  END wd_in[105]
  PIN wd_in[106]
    DIRECTION INPUT ;
    USE SIGNAL ;
    SHAPE ABUTMENT ;
    PORT
      LAYER M4 ;
      RECT 0.000 69.735 0.024 69.759 ;
    END
  END wd_in[106]
  PIN wd_in[107]
    DIRECTION INPUT ;
    USE SIGNAL ;
    SHAPE ABUTMENT ;
    PORT
      LAYER M4 ;
      RECT 0.000 70.023 0.024 70.047 ;
    END
  END wd_in[107]
  PIN wd_in[108]
    DIRECTION INPUT ;
    USE SIGNAL ;
    SHAPE ABUTMENT ;
    PORT
      LAYER M4 ;
      RECT 0.000 70.311 0.024 70.335 ;
    END
  END wd_in[108]
  PIN wd_in[109]
    DIRECTION INPUT ;
    USE SIGNAL ;
    SHAPE ABUTMENT ;
    PORT
      LAYER M4 ;
      RECT 0.000 70.599 0.024 70.623 ;
    END
  END wd_in[109]
  PIN wd_in[110]
    DIRECTION INPUT ;
    USE SIGNAL ;
    SHAPE ABUTMENT ;
    PORT
      LAYER M4 ;
      RECT 0.000 70.887 0.024 70.911 ;
    END
  END wd_in[110]
  PIN wd_in[111]
    DIRECTION INPUT ;
    USE SIGNAL ;
    SHAPE ABUTMENT ;
    PORT
      LAYER M4 ;
      RECT 0.000 71.175 0.024 71.199 ;
    END
  END wd_in[111]
  PIN wd_in[112]
    DIRECTION INPUT ;
    USE SIGNAL ;
    SHAPE ABUTMENT ;
    PORT
      LAYER M4 ;
      RECT 0.000 71.463 0.024 71.487 ;
    END
  END wd_in[112]
  PIN wd_in[113]
    DIRECTION INPUT ;
    USE SIGNAL ;
    SHAPE ABUTMENT ;
    PORT
      LAYER M4 ;
      RECT 0.000 71.751 0.024 71.775 ;
    END
  END wd_in[113]
  PIN wd_in[114]
    DIRECTION INPUT ;
    USE SIGNAL ;
    SHAPE ABUTMENT ;
    PORT
      LAYER M4 ;
      RECT 0.000 72.039 0.024 72.063 ;
    END
  END wd_in[114]
  PIN wd_in[115]
    DIRECTION INPUT ;
    USE SIGNAL ;
    SHAPE ABUTMENT ;
    PORT
      LAYER M4 ;
      RECT 0.000 72.327 0.024 72.351 ;
    END
  END wd_in[115]
  PIN wd_in[116]
    DIRECTION INPUT ;
    USE SIGNAL ;
    SHAPE ABUTMENT ;
    PORT
      LAYER M4 ;
      RECT 0.000 72.615 0.024 72.639 ;
    END
  END wd_in[116]
  PIN wd_in[117]
    DIRECTION INPUT ;
    USE SIGNAL ;
    SHAPE ABUTMENT ;
    PORT
      LAYER M4 ;
      RECT 0.000 72.903 0.024 72.927 ;
    END
  END wd_in[117]
  PIN wd_in[118]
    DIRECTION INPUT ;
    USE SIGNAL ;
    SHAPE ABUTMENT ;
    PORT
      LAYER M4 ;
      RECT 0.000 73.191 0.024 73.215 ;
    END
  END wd_in[118]
  PIN wd_in[119]
    DIRECTION INPUT ;
    USE SIGNAL ;
    SHAPE ABUTMENT ;
    PORT
      LAYER M4 ;
      RECT 0.000 73.479 0.024 73.503 ;
    END
  END wd_in[119]
  PIN wd_in[120]
    DIRECTION INPUT ;
    USE SIGNAL ;
    SHAPE ABUTMENT ;
    PORT
      LAYER M4 ;
      RECT 0.000 73.767 0.024 73.791 ;
    END
  END wd_in[120]
  PIN wd_in[121]
    DIRECTION INPUT ;
    USE SIGNAL ;
    SHAPE ABUTMENT ;
    PORT
      LAYER M4 ;
      RECT 0.000 74.055 0.024 74.079 ;
    END
  END wd_in[121]
  PIN wd_in[122]
    DIRECTION INPUT ;
    USE SIGNAL ;
    SHAPE ABUTMENT ;
    PORT
      LAYER M4 ;
      RECT 0.000 74.343 0.024 74.367 ;
    END
  END wd_in[122]
  PIN wd_in[123]
    DIRECTION INPUT ;
    USE SIGNAL ;
    SHAPE ABUTMENT ;
    PORT
      LAYER M4 ;
      RECT 0.000 74.631 0.024 74.655 ;
    END
  END wd_in[123]
  PIN wd_in[124]
    DIRECTION INPUT ;
    USE SIGNAL ;
    SHAPE ABUTMENT ;
    PORT
      LAYER M4 ;
      RECT 0.000 74.919 0.024 74.943 ;
    END
  END wd_in[124]
  PIN wd_in[125]
    DIRECTION INPUT ;
    USE SIGNAL ;
    SHAPE ABUTMENT ;
    PORT
      LAYER M4 ;
      RECT 0.000 75.207 0.024 75.231 ;
    END
  END wd_in[125]
  PIN wd_in[126]
    DIRECTION INPUT ;
    USE SIGNAL ;
    SHAPE ABUTMENT ;
    PORT
      LAYER M4 ;
      RECT 0.000 75.495 0.024 75.519 ;
    END
  END wd_in[126]
  PIN wd_in[127]
    DIRECTION INPUT ;
    USE SIGNAL ;
    SHAPE ABUTMENT ;
    PORT
      LAYER M4 ;
      RECT 0.000 75.783 0.024 75.807 ;
    END
  END wd_in[127]
  PIN addr_in[0]
    DIRECTION INPUT ;
    USE SIGNAL ;
    SHAPE ABUTMENT ;
    PORT
      LAYER M4 ;
      RECT 0.000 78.375 0.024 78.399 ;
    END
  END addr_in[0]
  PIN addr_in[1]
    DIRECTION INPUT ;
    USE SIGNAL ;
    SHAPE ABUTMENT ;
    PORT
      LAYER M4 ;
      RECT 0.000 78.663 0.024 78.687 ;
    END
  END addr_in[1]
  PIN addr_in[2]
    DIRECTION INPUT ;
    USE SIGNAL ;
    SHAPE ABUTMENT ;
    PORT
      LAYER M4 ;
      RECT 0.000 78.951 0.024 78.975 ;
    END
  END addr_in[2]
  PIN addr_in[3]
    DIRECTION INPUT ;
    USE SIGNAL ;
    SHAPE ABUTMENT ;
    PORT
      LAYER M4 ;
      RECT 0.000 79.239 0.024 79.263 ;
    END
  END addr_in[3]
  PIN addr_in[4]
    DIRECTION INPUT ;
    USE SIGNAL ;
    SHAPE ABUTMENT ;
    PORT
      LAYER M4 ;
      RECT 0.000 79.527 0.024 79.551 ;
    END
  END addr_in[4]
  PIN addr_in[5]
    DIRECTION INPUT ;
    USE SIGNAL ;
    SHAPE ABUTMENT ;
    PORT
      LAYER M4 ;
      RECT 0.000 79.815 0.024 79.839 ;
    END
  END addr_in[5]
  PIN addr_in[6]
    DIRECTION INPUT ;
    USE SIGNAL ;
    SHAPE ABUTMENT ;
    PORT
      LAYER M4 ;
      RECT 0.000 80.103 0.024 80.127 ;
    END
  END addr_in[6]
  PIN addr_in[7]
    DIRECTION INPUT ;
    USE SIGNAL ;
    SHAPE ABUTMENT ;
    PORT
      LAYER M4 ;
      RECT 0.000 80.391 0.024 80.415 ;
    END
  END addr_in[7]
  PIN we_in
    DIRECTION INPUT ;
    USE SIGNAL ;
    SHAPE ABUTMENT ;
    PORT
      LAYER M4 ;
      RECT 0.000 82.983 0.024 83.007 ;
    END
  END we_in
  PIN ce_in
    DIRECTION INPUT ;
    USE SIGNAL ;
    SHAPE ABUTMENT ;
    PORT
      LAYER M4 ;
      RECT 0.000 83.271 0.024 83.295 ;
    END
  END ce_in
  PIN clk
    DIRECTION INPUT ;
    USE SIGNAL ;
    SHAPE ABUTMENT ;
    PORT
      LAYER M4 ;
      RECT 0.000 83.559 0.024 83.583 ;
    END
  END clk
  PIN VSS
    DIRECTION INOUT ;
    USE GROUND ;
    PORT
      LAYER M4 ;
      RECT 0.048 0.000 16.672 0.096 ;
      RECT 0.048 0.768 16.672 0.864 ;
      RECT 0.048 1.536 16.672 1.632 ;
      RECT 0.048 2.304 16.672 2.400 ;
      RECT 0.048 3.072 16.672 3.168 ;
      RECT 0.048 3.840 16.672 3.936 ;
      RECT 0.048 4.608 16.672 4.704 ;
      RECT 0.048 5.376 16.672 5.472 ;
      RECT 0.048 6.144 16.672 6.240 ;
      RECT 0.048 6.912 16.672 7.008 ;
      RECT 0.048 7.680 16.672 7.776 ;
      RECT 0.048 8.448 16.672 8.544 ;
      RECT 0.048 9.216 16.672 9.312 ;
      RECT 0.048 9.984 16.672 10.080 ;
      RECT 0.048 10.752 16.672 10.848 ;
      RECT 0.048 11.520 16.672 11.616 ;
      RECT 0.048 12.288 16.672 12.384 ;
      RECT 0.048 13.056 16.672 13.152 ;
      RECT 0.048 13.824 16.672 13.920 ;
      RECT 0.048 14.592 16.672 14.688 ;
      RECT 0.048 15.360 16.672 15.456 ;
      RECT 0.048 16.128 16.672 16.224 ;
      RECT 0.048 16.896 16.672 16.992 ;
      RECT 0.048 17.664 16.672 17.760 ;
      RECT 0.048 18.432 16.672 18.528 ;
      RECT 0.048 19.200 16.672 19.296 ;
      RECT 0.048 19.968 16.672 20.064 ;
      RECT 0.048 20.736 16.672 20.832 ;
      RECT 0.048 21.504 16.672 21.600 ;
      RECT 0.048 22.272 16.672 22.368 ;
      RECT 0.048 23.040 16.672 23.136 ;
      RECT 0.048 23.808 16.672 23.904 ;
      RECT 0.048 24.576 16.672 24.672 ;
      RECT 0.048 25.344 16.672 25.440 ;
      RECT 0.048 26.112 16.672 26.208 ;
      RECT 0.048 26.880 16.672 26.976 ;
      RECT 0.048 27.648 16.672 27.744 ;
      RECT 0.048 28.416 16.672 28.512 ;
      RECT 0.048 29.184 16.672 29.280 ;
      RECT 0.048 29.952 16.672 30.048 ;
      RECT 0.048 30.720 16.672 30.816 ;
      RECT 0.048 31.488 16.672 31.584 ;
      RECT 0.048 32.256 16.672 32.352 ;
      RECT 0.048 33.024 16.672 33.120 ;
      RECT 0.048 33.792 16.672 33.888 ;
      RECT 0.048 34.560 16.672 34.656 ;
      RECT 0.048 35.328 16.672 35.424 ;
      RECT 0.048 36.096 16.672 36.192 ;
      RECT 0.048 36.864 16.672 36.960 ;
      RECT 0.048 37.632 16.672 37.728 ;
      RECT 0.048 38.400 16.672 38.496 ;
      RECT 0.048 39.168 16.672 39.264 ;
      RECT 0.048 39.936 16.672 40.032 ;
      RECT 0.048 40.704 16.672 40.800 ;
      RECT 0.048 41.472 16.672 41.568 ;
      RECT 0.048 42.240 16.672 42.336 ;
      RECT 0.048 43.008 16.672 43.104 ;
      RECT 0.048 43.776 16.672 43.872 ;
      RECT 0.048 44.544 16.672 44.640 ;
      RECT 0.048 45.312 16.672 45.408 ;
      RECT 0.048 46.080 16.672 46.176 ;
      RECT 0.048 46.848 16.672 46.944 ;
      RECT 0.048 47.616 16.672 47.712 ;
      RECT 0.048 48.384 16.672 48.480 ;
      RECT 0.048 49.152 16.672 49.248 ;
      RECT 0.048 49.920 16.672 50.016 ;
      RECT 0.048 50.688 16.672 50.784 ;
      RECT 0.048 51.456 16.672 51.552 ;
      RECT 0.048 52.224 16.672 52.320 ;
      RECT 0.048 52.992 16.672 53.088 ;
      RECT 0.048 53.760 16.672 53.856 ;
      RECT 0.048 54.528 16.672 54.624 ;
      RECT 0.048 55.296 16.672 55.392 ;
      RECT 0.048 56.064 16.672 56.160 ;
      RECT 0.048 56.832 16.672 56.928 ;
      RECT 0.048 57.600 16.672 57.696 ;
      RECT 0.048 58.368 16.672 58.464 ;
      RECT 0.048 59.136 16.672 59.232 ;
      RECT 0.048 59.904 16.672 60.000 ;
      RECT 0.048 60.672 16.672 60.768 ;
      RECT 0.048 61.440 16.672 61.536 ;
      RECT 0.048 62.208 16.672 62.304 ;
      RECT 0.048 62.976 16.672 63.072 ;
      RECT 0.048 63.744 16.672 63.840 ;
      RECT 0.048 64.512 16.672 64.608 ;
      RECT 0.048 65.280 16.672 65.376 ;
      RECT 0.048 66.048 16.672 66.144 ;
      RECT 0.048 66.816 16.672 66.912 ;
      RECT 0.048 67.584 16.672 67.680 ;
      RECT 0.048 68.352 16.672 68.448 ;
      RECT 0.048 69.120 16.672 69.216 ;
      RECT 0.048 69.888 16.672 69.984 ;
      RECT 0.048 70.656 16.672 70.752 ;
      RECT 0.048 71.424 16.672 71.520 ;
      RECT 0.048 72.192 16.672 72.288 ;
      RECT 0.048 72.960 16.672 73.056 ;
      RECT 0.048 73.728 16.672 73.824 ;
      RECT 0.048 74.496 16.672 74.592 ;
      RECT 0.048 75.264 16.672 75.360 ;
      RECT 0.048 76.032 16.672 76.128 ;
      RECT 0.048 76.800 16.672 76.896 ;
      RECT 0.048 77.568 16.672 77.664 ;
      RECT 0.048 78.336 16.672 78.432 ;
      RECT 0.048 79.104 16.672 79.200 ;
      RECT 0.048 79.872 16.672 79.968 ;
      RECT 0.048 80.640 16.672 80.736 ;
      RECT 0.048 81.408 16.672 81.504 ;
      RECT 0.048 82.176 16.672 82.272 ;
      RECT 0.048 82.944 16.672 83.040 ;
      RECT 0.048 83.712 16.672 83.808 ;
    END
  END VSS
  PIN VDD
    DIRECTION INOUT ;
    USE POWER ;
    PORT
      LAYER M4 ;
      RECT 0.048 0.384 16.672 0.480 ;
      RECT 0.048 1.152 16.672 1.248 ;
      RECT 0.048 1.920 16.672 2.016 ;
      RECT 0.048 2.688 16.672 2.784 ;
      RECT 0.048 3.456 16.672 3.552 ;
      RECT 0.048 4.224 16.672 4.320 ;
      RECT 0.048 4.992 16.672 5.088 ;
      RECT 0.048 5.760 16.672 5.856 ;
      RECT 0.048 6.528 16.672 6.624 ;
      RECT 0.048 7.296 16.672 7.392 ;
      RECT 0.048 8.064 16.672 8.160 ;
      RECT 0.048 8.832 16.672 8.928 ;
      RECT 0.048 9.600 16.672 9.696 ;
      RECT 0.048 10.368 16.672 10.464 ;
      RECT 0.048 11.136 16.672 11.232 ;
      RECT 0.048 11.904 16.672 12.000 ;
      RECT 0.048 12.672 16.672 12.768 ;
      RECT 0.048 13.440 16.672 13.536 ;
      RECT 0.048 14.208 16.672 14.304 ;
      RECT 0.048 14.976 16.672 15.072 ;
      RECT 0.048 15.744 16.672 15.840 ;
      RECT 0.048 16.512 16.672 16.608 ;
      RECT 0.048 17.280 16.672 17.376 ;
      RECT 0.048 18.048 16.672 18.144 ;
      RECT 0.048 18.816 16.672 18.912 ;
      RECT 0.048 19.584 16.672 19.680 ;
      RECT 0.048 20.352 16.672 20.448 ;
      RECT 0.048 21.120 16.672 21.216 ;
      RECT 0.048 21.888 16.672 21.984 ;
      RECT 0.048 22.656 16.672 22.752 ;
      RECT 0.048 23.424 16.672 23.520 ;
      RECT 0.048 24.192 16.672 24.288 ;
      RECT 0.048 24.960 16.672 25.056 ;
      RECT 0.048 25.728 16.672 25.824 ;
      RECT 0.048 26.496 16.672 26.592 ;
      RECT 0.048 27.264 16.672 27.360 ;
      RECT 0.048 28.032 16.672 28.128 ;
      RECT 0.048 28.800 16.672 28.896 ;
      RECT 0.048 29.568 16.672 29.664 ;
      RECT 0.048 30.336 16.672 30.432 ;
      RECT 0.048 31.104 16.672 31.200 ;
      RECT 0.048 31.872 16.672 31.968 ;
      RECT 0.048 32.640 16.672 32.736 ;
      RECT 0.048 33.408 16.672 33.504 ;
      RECT 0.048 34.176 16.672 34.272 ;
      RECT 0.048 34.944 16.672 35.040 ;
      RECT 0.048 35.712 16.672 35.808 ;
      RECT 0.048 36.480 16.672 36.576 ;
      RECT 0.048 37.248 16.672 37.344 ;
      RECT 0.048 38.016 16.672 38.112 ;
      RECT 0.048 38.784 16.672 38.880 ;
      RECT 0.048 39.552 16.672 39.648 ;
      RECT 0.048 40.320 16.672 40.416 ;
      RECT 0.048 41.088 16.672 41.184 ;
      RECT 0.048 41.856 16.672 41.952 ;
      RECT 0.048 42.624 16.672 42.720 ;
      RECT 0.048 43.392 16.672 43.488 ;
      RECT 0.048 44.160 16.672 44.256 ;
      RECT 0.048 44.928 16.672 45.024 ;
      RECT 0.048 45.696 16.672 45.792 ;
      RECT 0.048 46.464 16.672 46.560 ;
      RECT 0.048 47.232 16.672 47.328 ;
      RECT 0.048 48.000 16.672 48.096 ;
      RECT 0.048 48.768 16.672 48.864 ;
      RECT 0.048 49.536 16.672 49.632 ;
      RECT 0.048 50.304 16.672 50.400 ;
      RECT 0.048 51.072 16.672 51.168 ;
      RECT 0.048 51.840 16.672 51.936 ;
      RECT 0.048 52.608 16.672 52.704 ;
      RECT 0.048 53.376 16.672 53.472 ;
      RECT 0.048 54.144 16.672 54.240 ;
      RECT 0.048 54.912 16.672 55.008 ;
      RECT 0.048 55.680 16.672 55.776 ;
      RECT 0.048 56.448 16.672 56.544 ;
      RECT 0.048 57.216 16.672 57.312 ;
      RECT 0.048 57.984 16.672 58.080 ;
      RECT 0.048 58.752 16.672 58.848 ;
      RECT 0.048 59.520 16.672 59.616 ;
      RECT 0.048 60.288 16.672 60.384 ;
      RECT 0.048 61.056 16.672 61.152 ;
      RECT 0.048 61.824 16.672 61.920 ;
      RECT 0.048 62.592 16.672 62.688 ;
      RECT 0.048 63.360 16.672 63.456 ;
      RECT 0.048 64.128 16.672 64.224 ;
      RECT 0.048 64.896 16.672 64.992 ;
      RECT 0.048 65.664 16.672 65.760 ;
      RECT 0.048 66.432 16.672 66.528 ;
      RECT 0.048 67.200 16.672 67.296 ;
      RECT 0.048 67.968 16.672 68.064 ;
      RECT 0.048 68.736 16.672 68.832 ;
      RECT 0.048 69.504 16.672 69.600 ;
      RECT 0.048 70.272 16.672 70.368 ;
      RECT 0.048 71.040 16.672 71.136 ;
      RECT 0.048 71.808 16.672 71.904 ;
      RECT 0.048 72.576 16.672 72.672 ;
      RECT 0.048 73.344 16.672 73.440 ;
      RECT 0.048 74.112 16.672 74.208 ;
      RECT 0.048 74.880 16.672 74.976 ;
      RECT 0.048 75.648 16.672 75.744 ;
      RECT 0.048 76.416 16.672 76.512 ;
      RECT 0.048 77.184 16.672 77.280 ;
      RECT 0.048 77.952 16.672 78.048 ;
      RECT 0.048 78.720 16.672 78.816 ;
      RECT 0.048 79.488 16.672 79.584 ;
      RECT 0.048 80.256 16.672 80.352 ;
      RECT 0.048 81.024 16.672 81.120 ;
      RECT 0.048 81.792 16.672 81.888 ;
      RECT 0.048 82.560 16.672 82.656 ;
      RECT 0.048 83.328 16.672 83.424 ;
    END
  END VDD
  OBS
    LAYER M1 ;
    RECT 0 0 16.720 84.000 ;
    LAYER M2 ;
    RECT 0 0 16.720 84.000 ;
    LAYER M3 ;
    RECT 0.059 0.000 16.720 84.000 ;
    LAYER M4 ;
    RECT 0.059 0.000 16.720 84.000 ;
  END
END fakeram_256x128_bottom

END LIBRARY
